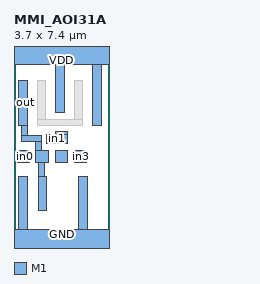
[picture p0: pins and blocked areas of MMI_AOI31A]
MACRO MMI_AOI31A
	CLASS CORE ;
	FOREIGN MMI_AOI31A 0 0 ;
	SIZE 3.7 BY 7.4 ;
	SYMMETRY X Y ;
	SITE CORE1 ;
	PIN out
		DIRECTION output ;
		USE SIGNAL ;
		PORT
			LAYER M1 ;
			RECT 0.18 4.545 0.52 6.305 ;
			LAYER M1 ;
			RECT 0.29 4.135 0.52 4.545 ;
			LAYER M1 ;
			RECT 0.29 3.905 1.055 4.135 ;
			LAYER M1 ;
			RECT 0.825 3.555 1.055 3.905 ;
			LAYER M1 ;
			RECT 0.825 3.105 1.335 3.555 ;
			LAYER M1 ;
			RECT 0.94 2.54 1.17 3.105 ;
			LAYER M1 ;
			RECT 0.94 1.24 1.28 2.54 ;
		END
		AntennaDiffArea 1.5916 ;
	END out
	PIN in1
		DIRECTION input ;
		USE SIGNAL ;
		PORT
			LAYER M1 ;
			RECT 1.625 4.19 2.075 4.295 ;
			LAYER M1 ;
			RECT 1.285 3.85 2.075 4.19 ;
			LAYER M1 ;
			RECT 1.625 3.845 2.075 3.85 ;
		END
		AntennaGateArea 0.5796 ;
	END in1
	PIN GND
		DIRECTION inout ;
		USE GROUND ;
		PORT
			LAYER M1 ;
			RECT 0.18 0.5 0.52 2.54 ;
			LAYER M1 ;
			RECT 2.52 0.5 2.86 2.54 ;
			LAYER M1 ;
			RECT 0 -0.5 3.7 0.5 ;
		END
	END GND
	PIN in2
		DIRECTION input ;
		USE SIGNAL ;
		PORT
			LAYER M1 ;
			RECT 1.625 3.105 2.075 3.555 ;
		END
		AntennaGateArea 0.5796 ;
	END in2
	PIN VDD
		DIRECTION inout ;
		USE POWER ;
		PORT
			LAYER M1 ;
			RECT 0 6.9 3.7 7.9 ;
			LAYER M1 ;
			RECT 1.62 5.025 1.96 6.9 ;
			LAYER M1 ;
			RECT 3.06 4.545 3.4 6.9 ;
		END
	END VDD
	PIN in3
		DIRECTION input ;
		USE SIGNAL ;
		PORT
			LAYER M1 ;
			RECT 2.365 3.105 2.815 3.555 ;
		END
		AntennaGateArea 0.5796 ;
	END in3
	PIN in0
		DIRECTION input ;
		USE SIGNAL ;
		PORT
			LAYER M1 ;
			RECT 0.145 3.105 0.595 3.555 ;
		END
		AntennaGateArea 0.414 ;
	END in0
	OBS
		LAYER M1 ;
		RECT 0.9 4.775 1.24 6.305 ;
		LAYER M1 ;
		RECT 2.34 4.775 2.68 6.305 ;
		LAYER M1 ;
		RECT 0.9 4.545 2.68 4.775 ;
	END
END MMI_AOI31A
